VERSION 5.7 ;
  NOWIREEXTENSIONATPIN ON ;
  DIVIDERCHAR "/" ;
  BUSBITCHARS "[]" ;
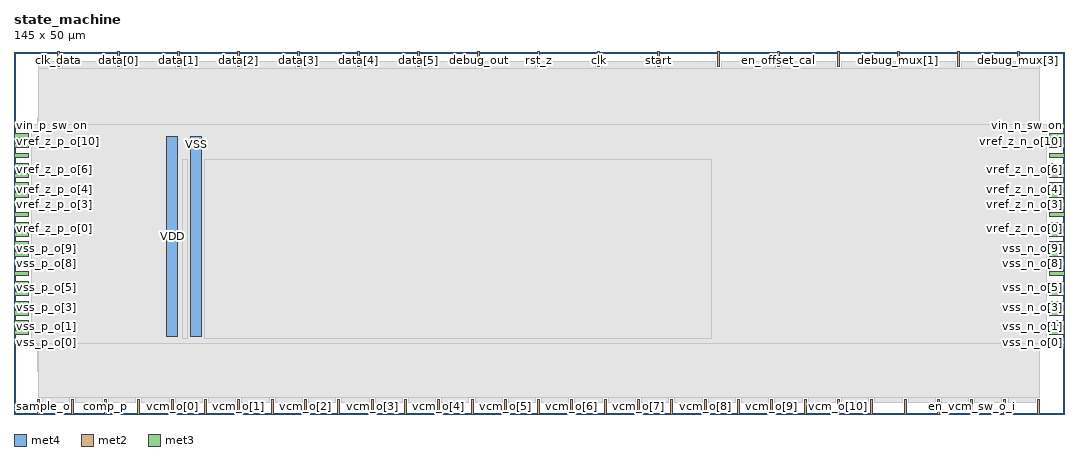
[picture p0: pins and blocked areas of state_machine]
MACRO state_machine
  CLASS BLOCK ;
  FOREIGN state_machine ;
  ORIGIN 0.000 0.000 ;
  SIZE 145.000 BY 50.000 ;
  PIN VDD
    DIRECTION INOUT ;
    USE POWER ;
    PORT
      LAYER met4 ;
        RECT 21.040 10.640 22.640 38.320 ;
    END
  END VDD
  PIN VSS
    DIRECTION INOUT ;
    USE GROUND ;
    PORT
      LAYER met4 ;
        RECT 24.340 10.640 25.940 38.320 ;
    END
  END VSS
  PIN clk
    DIRECTION INPUT ;
    USE SIGNAL ;
    ANTENNAGATEAREA 0.196500 ;
    PORT
      LAYER met2 ;
        RECT 80.590 48.000 80.870 50.000 ;
    END
  END clk
  PIN clk_data
    DIRECTION OUTPUT ;
    USE SIGNAL ;
    ANTENNADIFFAREA 0.795200 ;
    PORT
      LAYER met2 ;
        RECT 6.070 48.000 6.350 50.000 ;
    END
  END clk_data
  PIN comp_n
    DIRECTION INPUT ;
    USE SIGNAL ;
    ANTENNAGATEAREA 0.196500 ;
    PORT
      LAYER met2 ;
        RECT 17.110 0.000 17.390 2.000 ;
    END
  END comp_n
  PIN comp_p
    DIRECTION INPUT ;
    USE SIGNAL ;
    ANTENNAGATEAREA 0.159000 ;
    PORT
      LAYER met2 ;
        RECT 12.510 0.000 12.790 2.000 ;
    END
  END comp_p
  PIN data[0]
    DIRECTION OUTPUT ;
    USE SIGNAL ;
    ANTENNADIFFAREA 0.795200 ;
    PORT
      LAYER met2 ;
        RECT 14.350 48.000 14.630 50.000 ;
    END
  END data[0]
  PIN data[1]
    DIRECTION OUTPUT ;
    USE SIGNAL ;
    ANTENNADIFFAREA 0.795200 ;
    PORT
      LAYER met2 ;
        RECT 22.630 48.000 22.910 50.000 ;
    END
  END data[1]
  PIN data[2]
    DIRECTION OUTPUT ;
    USE SIGNAL ;
    ANTENNADIFFAREA 0.795200 ;
    PORT
      LAYER met2 ;
        RECT 30.910 48.000 31.190 50.000 ;
    END
  END data[2]
  PIN data[3]
    DIRECTION OUTPUT ;
    USE SIGNAL ;
    ANTENNADIFFAREA 0.795200 ;
    PORT
      LAYER met2 ;
        RECT 39.190 48.000 39.470 50.000 ;
    END
  END data[3]
  PIN data[4]
    DIRECTION OUTPUT ;
    USE SIGNAL ;
    ANTENNADIFFAREA 0.795200 ;
    PORT
      LAYER met2 ;
        RECT 47.470 48.000 47.750 50.000 ;
    END
  END data[4]
  PIN data[5]
    DIRECTION OUTPUT ;
    USE SIGNAL ;
    ANTENNADIFFAREA 0.795200 ;
    PORT
      LAYER met2 ;
        RECT 55.750 48.000 56.030 50.000 ;
    END
  END data[5]
  PIN debug_mux[0]
    DIRECTION INPUT ;
    USE SIGNAL ;
    ANTENNAGATEAREA 0.159000 ;
    PORT
      LAYER met2 ;
        RECT 113.710 48.000 113.990 50.000 ;
    END
  END debug_mux[0]
  PIN debug_mux[1]
    DIRECTION INPUT ;
    USE SIGNAL ;
    ANTENNAGATEAREA 0.159000 ;
    PORT
      LAYER met2 ;
        RECT 121.990 48.000 122.270 50.000 ;
    END
  END debug_mux[1]
  PIN debug_mux[2]
    DIRECTION INPUT ;
    USE SIGNAL ;
    ANTENNAGATEAREA 0.196500 ;
    PORT
      LAYER met2 ;
        RECT 130.270 48.000 130.550 50.000 ;
    END
  END debug_mux[2]
  PIN debug_mux[3]
    DIRECTION INPUT ;
    USE SIGNAL ;
    ANTENNAGATEAREA 0.196500 ;
    PORT
      LAYER met2 ;
        RECT 138.550 48.000 138.830 50.000 ;
    END
  END debug_mux[3]
  PIN debug_out
    DIRECTION OUTPUT ;
    USE SIGNAL ;
    ANTENNADIFFAREA 0.795200 ;
    PORT
      LAYER met2 ;
        RECT 64.030 48.000 64.310 50.000 ;
    END
  END debug_out
  PIN en_comp
    DIRECTION OUTPUT ;
    USE SIGNAL ;
    ANTENNADIFFAREA 0.445500 ;
    PORT
      LAYER met2 ;
        RECT 7.910 0.000 8.190 2.000 ;
    END
  END en_comp
  PIN en_offset_cal
    DIRECTION INPUT ;
    USE SIGNAL ;
    ANTENNAGATEAREA 0.196500 ;
    PORT
      LAYER met2 ;
        RECT 105.430 48.000 105.710 50.000 ;
    END
  END en_offset_cal
  PIN en_offset_cal_o
    DIRECTION OUTPUT ;
    USE SIGNAL ;
    ANTENNADIFFAREA 0.795200 ;
    PORT
      LAYER met2 ;
        RECT 141.310 0.000 141.590 2.000 ;
    END
  END en_offset_cal_o
  PIN en_vcm_sw_o
    DIRECTION OUTPUT ;
    USE SIGNAL ;
    ANTENNADIFFAREA 0.445500 ;
    PORT
      LAYER met2 ;
        RECT 127.510 0.000 127.790 2.000 ;
    END
  END en_vcm_sw_o
  PIN en_vcm_sw_o_i
    DIRECTION INPUT ;
    USE SIGNAL ;
    ANTENNAGATEAREA 0.196500 ;
    PORT
      LAYER met2 ;
        RECT 132.110 0.000 132.390 2.000 ;
    END
  END en_vcm_sw_o_i
  PIN offset_cal_cycle
    DIRECTION OUTPUT ;
    USE SIGNAL ;
    ANTENNADIFFAREA 0.445500 ;
    PORT
      LAYER met2 ;
        RECT 136.710 0.000 136.990 2.000 ;
    END
  END offset_cal_cycle
  PIN rst_z
    DIRECTION INPUT ;
    USE SIGNAL ;
    ANTENNAGATEAREA 0.196500 ;
    PORT
      LAYER met2 ;
        RECT 72.310 48.000 72.590 50.000 ;
    END
  END rst_z
  PIN sample_o
    DIRECTION OUTPUT ;
    USE SIGNAL ;
    ANTENNADIFFAREA 0.795200 ;
    PORT
      LAYER met2 ;
        RECT 3.310 0.000 3.590 2.000 ;
    END
  END sample_o
  PIN single_ended
    DIRECTION INPUT ;
    USE SIGNAL ;
    ANTENNAGATEAREA 0.196500 ;
    PORT
      LAYER met2 ;
        RECT 97.150 48.000 97.430 50.000 ;
    END
  END single_ended
  PIN start
    DIRECTION INPUT ;
    USE SIGNAL ;
    ANTENNAGATEAREA 0.196500 ;
    PORT
      LAYER met2 ;
        RECT 88.870 48.000 89.150 50.000 ;
    END
  END start
  PIN vcm_dummy_o
    DIRECTION OUTPUT ;
    USE SIGNAL ;
    ANTENNADIFFAREA 0.445500 ;
    PORT
      LAYER met2 ;
        RECT 122.910 0.000 123.190 2.000 ;
    END
  END vcm_dummy_o
  PIN vcm_o[0]
    DIRECTION OUTPUT ;
    USE SIGNAL ;
    ANTENNADIFFAREA 0.445500 ;
    PORT
      LAYER met2 ;
        RECT 21.710 0.000 21.990 2.000 ;
    END
  END vcm_o[0]
  PIN vcm_o[10]
    DIRECTION OUTPUT ;
    USE SIGNAL ;
    ANTENNADIFFAREA 0.445500 ;
    PORT
      LAYER met2 ;
        RECT 113.710 0.000 113.990 2.000 ;
    END
  END vcm_o[10]
  PIN vcm_o[1]
    DIRECTION OUTPUT ;
    USE SIGNAL ;
    ANTENNADIFFAREA 0.445500 ;
    PORT
      LAYER met2 ;
        RECT 30.910 0.000 31.190 2.000 ;
    END
  END vcm_o[1]
  PIN vcm_o[2]
    DIRECTION OUTPUT ;
    USE SIGNAL ;
    ANTENNADIFFAREA 0.445500 ;
    PORT
      LAYER met2 ;
        RECT 40.110 0.000 40.390 2.000 ;
    END
  END vcm_o[2]
  PIN vcm_o[3]
    DIRECTION OUTPUT ;
    USE SIGNAL ;
    ANTENNADIFFAREA 0.445500 ;
    PORT
      LAYER met2 ;
        RECT 49.310 0.000 49.590 2.000 ;
    END
  END vcm_o[3]
  PIN vcm_o[4]
    DIRECTION OUTPUT ;
    USE SIGNAL ;
    ANTENNADIFFAREA 0.445500 ;
    PORT
      LAYER met2 ;
        RECT 58.510 0.000 58.790 2.000 ;
    END
  END vcm_o[4]
  PIN vcm_o[5]
    DIRECTION OUTPUT ;
    USE SIGNAL ;
    ANTENNADIFFAREA 0.445500 ;
    PORT
      LAYER met2 ;
        RECT 67.710 0.000 67.990 2.000 ;
    END
  END vcm_o[5]
  PIN vcm_o[6]
    DIRECTION OUTPUT ;
    USE SIGNAL ;
    ANTENNADIFFAREA 0.445500 ;
    PORT
      LAYER met2 ;
        RECT 76.910 0.000 77.190 2.000 ;
    END
  END vcm_o[6]
  PIN vcm_o[7]
    DIRECTION OUTPUT ;
    USE SIGNAL ;
    ANTENNADIFFAREA 0.445500 ;
    PORT
      LAYER met2 ;
        RECT 86.110 0.000 86.390 2.000 ;
    END
  END vcm_o[7]
  PIN vcm_o[8]
    DIRECTION OUTPUT ;
    USE SIGNAL ;
    ANTENNADIFFAREA 0.445500 ;
    PORT
      LAYER met2 ;
        RECT 95.310 0.000 95.590 2.000 ;
    END
  END vcm_o[8]
  PIN vcm_o[9]
    DIRECTION OUTPUT ;
    USE SIGNAL ;
    ANTENNADIFFAREA 0.445500 ;
    PORT
      LAYER met2 ;
        RECT 104.510 0.000 104.790 2.000 ;
    END
  END vcm_o[9]
  PIN vcm_o_i[0]
    DIRECTION INPUT ;
    USE SIGNAL ;
    ANTENNAGATEAREA 0.196500 ;
    PORT
      LAYER met2 ;
        RECT 26.310 0.000 26.590 2.000 ;
    END
  END vcm_o_i[0]
  PIN vcm_o_i[10]
    DIRECTION INPUT ;
    USE SIGNAL ;
    ANTENNAGATEAREA 0.196500 ;
    PORT
      LAYER met2 ;
        RECT 118.310 0.000 118.590 2.000 ;
    END
  END vcm_o_i[10]
  PIN vcm_o_i[1]
    DIRECTION INPUT ;
    USE SIGNAL ;
    ANTENNAGATEAREA 0.196500 ;
    PORT
      LAYER met2 ;
        RECT 35.510 0.000 35.790 2.000 ;
    END
  END vcm_o_i[1]
  PIN vcm_o_i[2]
    DIRECTION INPUT ;
    USE SIGNAL ;
    ANTENNAGATEAREA 0.196500 ;
    PORT
      LAYER met2 ;
        RECT 44.710 0.000 44.990 2.000 ;
    END
  END vcm_o_i[2]
  PIN vcm_o_i[3]
    DIRECTION INPUT ;
    USE SIGNAL ;
    ANTENNAGATEAREA 0.196500 ;
    PORT
      LAYER met2 ;
        RECT 53.910 0.000 54.190 2.000 ;
    END
  END vcm_o_i[3]
  PIN vcm_o_i[4]
    DIRECTION INPUT ;
    USE SIGNAL ;
    ANTENNAGATEAREA 0.196500 ;
    PORT
      LAYER met2 ;
        RECT 63.110 0.000 63.390 2.000 ;
    END
  END vcm_o_i[4]
  PIN vcm_o_i[5]
    DIRECTION INPUT ;
    USE SIGNAL ;
    ANTENNAGATEAREA 0.196500 ;
    PORT
      LAYER met2 ;
        RECT 72.310 0.000 72.590 2.000 ;
    END
  END vcm_o_i[5]
  PIN vcm_o_i[6]
    DIRECTION INPUT ;
    USE SIGNAL ;
    ANTENNAGATEAREA 0.196500 ;
    PORT
      LAYER met2 ;
        RECT 81.510 0.000 81.790 2.000 ;
    END
  END vcm_o_i[6]
  PIN vcm_o_i[7]
    DIRECTION INPUT ;
    USE SIGNAL ;
    ANTENNAGATEAREA 0.196500 ;
    PORT
      LAYER met2 ;
        RECT 90.710 0.000 90.990 2.000 ;
    END
  END vcm_o_i[7]
  PIN vcm_o_i[8]
    DIRECTION INPUT ;
    USE SIGNAL ;
    ANTENNAGATEAREA 0.196500 ;
    PORT
      LAYER met2 ;
        RECT 99.910 0.000 100.190 2.000 ;
    END
  END vcm_o_i[8]
  PIN vcm_o_i[9]
    DIRECTION INPUT ;
    USE SIGNAL ;
    ANTENNAGATEAREA 0.196500 ;
    PORT
      LAYER met2 ;
        RECT 109.110 0.000 109.390 2.000 ;
    END
  END vcm_o_i[9]
  PIN vin_n_sw_on
    DIRECTION INPUT ;
    USE SIGNAL ;
    ANTENNAGATEAREA 0.196500 ;
    PORT
      LAYER met3 ;
        RECT 143.000 39.480 145.000 40.080 ;
    END
  END vin_n_sw_on
  PIN vin_p_sw_on
    DIRECTION INPUT ;
    USE SIGNAL ;
    ANTENNAGATEAREA 0.196500 ;
    PORT
      LAYER met3 ;
        RECT 0.000 39.480 2.000 40.080 ;
    END
  END vin_p_sw_on
  PIN vref_z_n_o[0]
    DIRECTION OUTPUT ;
    USE SIGNAL ;
    ANTENNADIFFAREA 0.445500 ;
    PORT
      LAYER met3 ;
        RECT 143.000 24.520 145.000 25.120 ;
    END
  END vref_z_n_o[0]
  PIN vref_z_n_o[10]
    DIRECTION OUTPUT ;
    USE SIGNAL ;
    ANTENNADIFFAREA 0.445500 ;
    PORT
      LAYER met3 ;
        RECT 143.000 38.120 145.000 38.720 ;
    END
  END vref_z_n_o[10]
  PIN vref_z_n_o[1]
    DIRECTION OUTPUT ;
    USE SIGNAL ;
    ANTENNADIFFAREA 0.445500 ;
    PORT
      LAYER met3 ;
        RECT 143.000 25.880 145.000 26.480 ;
    END
  END vref_z_n_o[1]
  PIN vref_z_n_o[2]
    DIRECTION OUTPUT ;
    USE SIGNAL ;
    ANTENNADIFFAREA 0.445500 ;
    PORT
      LAYER met3 ;
        RECT 143.000 27.240 145.000 27.840 ;
    END
  END vref_z_n_o[2]
  PIN vref_z_n_o[3]
    DIRECTION OUTPUT ;
    USE SIGNAL ;
    ANTENNADIFFAREA 0.445500 ;
    PORT
      LAYER met3 ;
        RECT 143.000 28.600 145.000 29.200 ;
    END
  END vref_z_n_o[3]
  PIN vref_z_n_o[4]
    DIRECTION OUTPUT ;
    USE SIGNAL ;
    ANTENNADIFFAREA 0.445500 ;
    PORT
      LAYER met3 ;
        RECT 143.000 29.960 145.000 30.560 ;
    END
  END vref_z_n_o[4]
  PIN vref_z_n_o[5]
    DIRECTION OUTPUT ;
    USE SIGNAL ;
    ANTENNADIFFAREA 0.445500 ;
    PORT
      LAYER met3 ;
        RECT 143.000 31.320 145.000 31.920 ;
    END
  END vref_z_n_o[5]
  PIN vref_z_n_o[6]
    DIRECTION OUTPUT ;
    USE SIGNAL ;
    ANTENNADIFFAREA 0.445500 ;
    PORT
      LAYER met3 ;
        RECT 143.000 32.680 145.000 33.280 ;
    END
  END vref_z_n_o[6]
  PIN vref_z_n_o[7]
    DIRECTION OUTPUT ;
    USE SIGNAL ;
    ANTENNADIFFAREA 0.445500 ;
    PORT
      LAYER met3 ;
        RECT 143.000 34.040 145.000 34.640 ;
    END
  END vref_z_n_o[7]
  PIN vref_z_n_o[8]
    DIRECTION OUTPUT ;
    USE SIGNAL ;
    ANTENNADIFFAREA 0.445500 ;
    PORT
      LAYER met3 ;
        RECT 143.000 35.400 145.000 36.000 ;
    END
  END vref_z_n_o[8]
  PIN vref_z_n_o[9]
    DIRECTION OUTPUT ;
    USE SIGNAL ;
    ANTENNADIFFAREA 0.445500 ;
    PORT
      LAYER met3 ;
        RECT 143.000 36.760 145.000 37.360 ;
    END
  END vref_z_n_o[9]
  PIN vref_z_p_o[0]
    DIRECTION OUTPUT ;
    USE SIGNAL ;
    ANTENNADIFFAREA 0.445500 ;
    PORT
      LAYER met3 ;
        RECT 0.000 24.520 2.000 25.120 ;
    END
  END vref_z_p_o[0]
  PIN vref_z_p_o[10]
    DIRECTION OUTPUT ;
    USE SIGNAL ;
    ANTENNADIFFAREA 0.445500 ;
    PORT
      LAYER met3 ;
        RECT 0.000 38.120 2.000 38.720 ;
    END
  END vref_z_p_o[10]
  PIN vref_z_p_o[1]
    DIRECTION OUTPUT ;
    USE SIGNAL ;
    ANTENNADIFFAREA 0.445500 ;
    PORT
      LAYER met3 ;
        RECT 0.000 25.880 2.000 26.480 ;
    END
  END vref_z_p_o[1]
  PIN vref_z_p_o[2]
    DIRECTION OUTPUT ;
    USE SIGNAL ;
    ANTENNADIFFAREA 0.445500 ;
    PORT
      LAYER met3 ;
        RECT 0.000 27.240 2.000 27.840 ;
    END
  END vref_z_p_o[2]
  PIN vref_z_p_o[3]
    DIRECTION OUTPUT ;
    USE SIGNAL ;
    ANTENNADIFFAREA 0.445500 ;
    PORT
      LAYER met3 ;
        RECT 0.000 28.600 2.000 29.200 ;
    END
  END vref_z_p_o[3]
  PIN vref_z_p_o[4]
    DIRECTION OUTPUT ;
    USE SIGNAL ;
    ANTENNADIFFAREA 0.445500 ;
    PORT
      LAYER met3 ;
        RECT 0.000 29.960 2.000 30.560 ;
    END
  END vref_z_p_o[4]
  PIN vref_z_p_o[5]
    DIRECTION OUTPUT ;
    USE SIGNAL ;
    ANTENNADIFFAREA 0.445500 ;
    PORT
      LAYER met3 ;
        RECT 0.000 31.320 2.000 31.920 ;
    END
  END vref_z_p_o[5]
  PIN vref_z_p_o[6]
    DIRECTION OUTPUT ;
    USE SIGNAL ;
    ANTENNADIFFAREA 0.445500 ;
    PORT
      LAYER met3 ;
        RECT 0.000 32.680 2.000 33.280 ;
    END
  END vref_z_p_o[6]
  PIN vref_z_p_o[7]
    DIRECTION OUTPUT ;
    USE SIGNAL ;
    ANTENNADIFFAREA 0.445500 ;
    PORT
      LAYER met3 ;
        RECT 0.000 34.040 2.000 34.640 ;
    END
  END vref_z_p_o[7]
  PIN vref_z_p_o[8]
    DIRECTION OUTPUT ;
    USE SIGNAL ;
    ANTENNADIFFAREA 0.445500 ;
    PORT
      LAYER met3 ;
        RECT 0.000 35.400 2.000 36.000 ;
    END
  END vref_z_p_o[8]
  PIN vref_z_p_o[9]
    DIRECTION OUTPUT ;
    USE SIGNAL ;
    ANTENNADIFFAREA 0.445500 ;
    PORT
      LAYER met3 ;
        RECT 0.000 36.760 2.000 37.360 ;
    END
  END vref_z_p_o[9]
  PIN vss_n_o[0]
    DIRECTION OUTPUT ;
    USE SIGNAL ;
    ANTENNADIFFAREA 0.445500 ;
    PORT
      LAYER met3 ;
        RECT 143.000 9.560 145.000 10.160 ;
    END
  END vss_n_o[0]
  PIN vss_n_o[10]
    DIRECTION OUTPUT ;
    USE SIGNAL ;
    ANTENNADIFFAREA 0.445500 ;
    PORT
      LAYER met3 ;
        RECT 143.000 23.160 145.000 23.760 ;
    END
  END vss_n_o[10]
  PIN vss_n_o[1]
    DIRECTION OUTPUT ;
    USE SIGNAL ;
    ANTENNADIFFAREA 0.445500 ;
    PORT
      LAYER met3 ;
        RECT 143.000 10.920 145.000 11.520 ;
    END
  END vss_n_o[1]
  PIN vss_n_o[2]
    DIRECTION OUTPUT ;
    USE SIGNAL ;
    ANTENNADIFFAREA 0.445500 ;
    PORT
      LAYER met3 ;
        RECT 143.000 12.280 145.000 12.880 ;
    END
  END vss_n_o[2]
  PIN vss_n_o[3]
    DIRECTION OUTPUT ;
    USE SIGNAL ;
    ANTENNADIFFAREA 0.445500 ;
    PORT
      LAYER met3 ;
        RECT 143.000 13.640 145.000 14.240 ;
    END
  END vss_n_o[3]
  PIN vss_n_o[4]
    DIRECTION OUTPUT ;
    USE SIGNAL ;
    ANTENNADIFFAREA 0.445500 ;
    PORT
      LAYER met3 ;
        RECT 143.000 15.000 145.000 15.600 ;
    END
  END vss_n_o[4]
  PIN vss_n_o[5]
    DIRECTION OUTPUT ;
    USE SIGNAL ;
    ANTENNADIFFAREA 0.445500 ;
    PORT
      LAYER met3 ;
        RECT 143.000 16.360 145.000 16.960 ;
    END
  END vss_n_o[5]
  PIN vss_n_o[6]
    DIRECTION OUTPUT ;
    USE SIGNAL ;
    ANTENNADIFFAREA 0.445500 ;
    PORT
      LAYER met3 ;
        RECT 143.000 17.720 145.000 18.320 ;
    END
  END vss_n_o[6]
  PIN vss_n_o[7]
    DIRECTION OUTPUT ;
    USE SIGNAL ;
    ANTENNADIFFAREA 0.445500 ;
    PORT
      LAYER met3 ;
        RECT 143.000 19.080 145.000 19.680 ;
    END
  END vss_n_o[7]
  PIN vss_n_o[8]
    DIRECTION OUTPUT ;
    USE SIGNAL ;
    ANTENNADIFFAREA 0.445500 ;
    PORT
      LAYER met3 ;
        RECT 143.000 20.440 145.000 21.040 ;
    END
  END vss_n_o[8]
  PIN vss_n_o[9]
    DIRECTION OUTPUT ;
    USE SIGNAL ;
    ANTENNADIFFAREA 0.445500 ;
    PORT
      LAYER met3 ;
        RECT 143.000 21.800 145.000 22.400 ;
    END
  END vss_n_o[9]
  PIN vss_p_o[0]
    DIRECTION OUTPUT ;
    USE SIGNAL ;
    ANTENNADIFFAREA 0.445500 ;
    PORT
      LAYER met3 ;
        RECT 0.000 9.560 2.000 10.160 ;
    END
  END vss_p_o[0]
  PIN vss_p_o[10]
    DIRECTION OUTPUT ;
    USE SIGNAL ;
    ANTENNADIFFAREA 0.445500 ;
    PORT
      LAYER met3 ;
        RECT 0.000 23.160 2.000 23.760 ;
    END
  END vss_p_o[10]
  PIN vss_p_o[1]
    DIRECTION OUTPUT ;
    USE SIGNAL ;
    ANTENNADIFFAREA 0.445500 ;
    PORT
      LAYER met3 ;
        RECT 0.000 10.920 2.000 11.520 ;
    END
  END vss_p_o[1]
  PIN vss_p_o[2]
    DIRECTION OUTPUT ;
    USE SIGNAL ;
    ANTENNADIFFAREA 0.445500 ;
    PORT
      LAYER met3 ;
        RECT 0.000 12.280 2.000 12.880 ;
    END
  END vss_p_o[2]
  PIN vss_p_o[3]
    DIRECTION OUTPUT ;
    USE SIGNAL ;
    ANTENNADIFFAREA 0.445500 ;
    PORT
      LAYER met3 ;
        RECT 0.000 13.640 2.000 14.240 ;
    END
  END vss_p_o[3]
  PIN vss_p_o[4]
    DIRECTION OUTPUT ;
    USE SIGNAL ;
    ANTENNADIFFAREA 0.445500 ;
    PORT
      LAYER met3 ;
        RECT 0.000 15.000 2.000 15.600 ;
    END
  END vss_p_o[4]
  PIN vss_p_o[5]
    DIRECTION OUTPUT ;
    USE SIGNAL ;
    ANTENNADIFFAREA 0.445500 ;
    PORT
      LAYER met3 ;
        RECT 0.000 16.360 2.000 16.960 ;
    END
  END vss_p_o[5]
  PIN vss_p_o[6]
    DIRECTION OUTPUT ;
    USE SIGNAL ;
    ANTENNADIFFAREA 0.445500 ;
    PORT
      LAYER met3 ;
        RECT 0.000 17.720 2.000 18.320 ;
    END
  END vss_p_o[6]
  PIN vss_p_o[7]
    DIRECTION OUTPUT ;
    USE SIGNAL ;
    ANTENNADIFFAREA 0.445500 ;
    PORT
      LAYER met3 ;
        RECT 0.000 19.080 2.000 19.680 ;
    END
  END vss_p_o[7]
  PIN vss_p_o[8]
    DIRECTION OUTPUT ;
    USE SIGNAL ;
    ANTENNADIFFAREA 0.445500 ;
    PORT
      LAYER met3 ;
        RECT 0.000 20.440 2.000 21.040 ;
    END
  END vss_p_o[8]
  PIN vss_p_o[9]
    DIRECTION OUTPUT ;
    USE SIGNAL ;
    ANTENNADIFFAREA 0.445500 ;
    PORT
      LAYER met3 ;
        RECT 0.000 21.800 2.000 22.400 ;
    END
  END vss_p_o[9]
  OBS
      LAYER li1 ;
        RECT 5.520 10.795 139.380 38.165 ;
      LAYER met1 ;
        RECT 3.290 5.820 141.610 40.760 ;
      LAYER met2 ;
        RECT 3.320 47.720 5.790 48.690 ;
        RECT 6.630 47.720 14.070 48.690 ;
        RECT 14.910 47.720 22.350 48.690 ;
        RECT 23.190 47.720 30.630 48.690 ;
        RECT 31.470 47.720 38.910 48.690 ;
        RECT 39.750 47.720 47.190 48.690 ;
        RECT 48.030 47.720 55.470 48.690 ;
        RECT 56.310 47.720 63.750 48.690 ;
        RECT 64.590 47.720 72.030 48.690 ;
        RECT 72.870 47.720 80.310 48.690 ;
        RECT 81.150 47.720 88.590 48.690 ;
        RECT 89.430 47.720 96.870 48.690 ;
        RECT 97.710 47.720 105.150 48.690 ;
        RECT 105.990 47.720 113.430 48.690 ;
        RECT 114.270 47.720 121.710 48.690 ;
        RECT 122.550 47.720 129.990 48.690 ;
        RECT 130.830 47.720 138.270 48.690 ;
        RECT 139.110 47.720 141.580 48.690 ;
        RECT 3.320 2.280 141.580 47.720 ;
        RECT 3.870 1.630 7.630 2.280 ;
        RECT 8.470 1.630 12.230 2.280 ;
        RECT 13.070 1.630 16.830 2.280 ;
        RECT 17.670 1.630 21.430 2.280 ;
        RECT 22.270 1.630 26.030 2.280 ;
        RECT 26.870 1.630 30.630 2.280 ;
        RECT 31.470 1.630 35.230 2.280 ;
        RECT 36.070 1.630 39.830 2.280 ;
        RECT 40.670 1.630 44.430 2.280 ;
        RECT 45.270 1.630 49.030 2.280 ;
        RECT 49.870 1.630 53.630 2.280 ;
        RECT 54.470 1.630 58.230 2.280 ;
        RECT 59.070 1.630 62.830 2.280 ;
        RECT 63.670 1.630 67.430 2.280 ;
        RECT 68.270 1.630 72.030 2.280 ;
        RECT 72.870 1.630 76.630 2.280 ;
        RECT 77.470 1.630 81.230 2.280 ;
        RECT 82.070 1.630 85.830 2.280 ;
        RECT 86.670 1.630 90.430 2.280 ;
        RECT 91.270 1.630 95.030 2.280 ;
        RECT 95.870 1.630 99.630 2.280 ;
        RECT 100.470 1.630 104.230 2.280 ;
        RECT 105.070 1.630 108.830 2.280 ;
        RECT 109.670 1.630 113.430 2.280 ;
        RECT 114.270 1.630 118.030 2.280 ;
        RECT 118.870 1.630 122.630 2.280 ;
        RECT 123.470 1.630 127.230 2.280 ;
        RECT 128.070 1.630 131.830 2.280 ;
        RECT 132.670 1.630 136.430 2.280 ;
        RECT 137.270 1.630 141.030 2.280 ;
      LAYER met3 ;
        RECT 2.400 9.695 142.600 39.945 ;
      LAYER met4 ;
        RECT 23.295 10.375 23.940 35.185 ;
        RECT 26.340 10.375 96.305 35.185 ;
  END
END state_machine
END LIBRARY

